VERSION 5.8 ;
BUSBITCHARS "[]" ;
DIVIDERCHAR "/" ;

PROPERTYDEFINITIONS
  MACRO SDLpower STRING ;
  MACRO SDLground STRING ;
  MACRO SDLglobal STRING ;
END PROPERTYDEFINITIONS

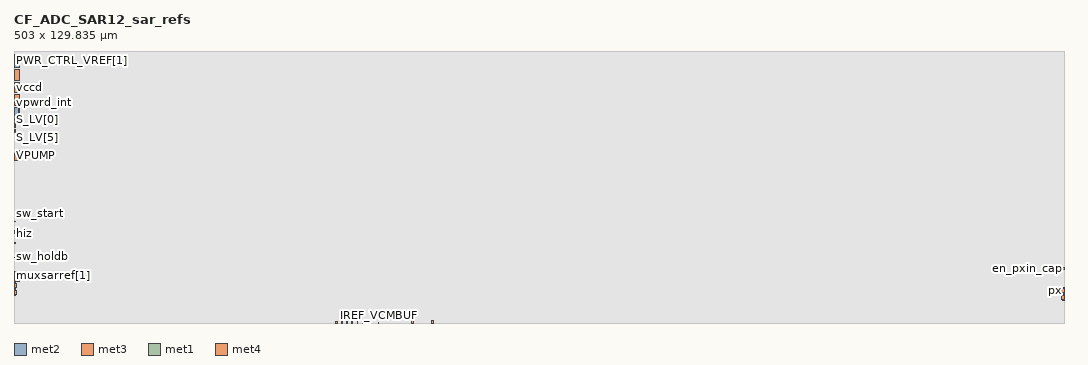
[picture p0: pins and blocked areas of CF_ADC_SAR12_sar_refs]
MACRO CF_ADC_SAR12_sar_refs
  ORIGIN 0 0 ;
  FOREIGN CF_ADC_SAR12_sar_refs 0 0 ;
  SIZE 503 BY 129.835 ;
  PIN vdda
    DIRECTION INOUT ;
    USE POWER ;
    PORT
      LAYER met2 ;
        RECT 0 122.39 2.5 127.085 ;
      LAYER met3 ;
        RECT 0 122.39 2.5 127.14 ;
    END
  END vdda
  PIN vda_int
    DIRECTION OUTPUT ;
    USE POWER ;
    PORT
      LAYER met2 ;
        RECT 0 116.39 2.5 121.39 ;
      LAYER met3 ;
        RECT 0 116.39 2.5 121.39 ;
    END
  END vda_int
  PIN vccd
    DIRECTION INOUT ;
    USE POWER ;
    PORT
      LAYER met2 ;
        RECT 0 110.39 2.5 115.39 ;
      LAYER met3 ;
        RECT 0 110.39 2.5 115.39 ;
    END
  END vccd
  PIN vpwrd_int
    DIRECTION OUTPUT ;
    USE POWER ;
    PORT
      LAYER met2 ;
        RECT 0 104.39 2.5 109.39 ;
      LAYER met3 ;
        RECT 0 104.39 2.5 109.39 ;
    END
  END vpwrd_int
  PIN VPUMP
    DIRECTION INOUT ;
    USE POWER ;
    PORT
      LAYER met2 ;
        RECT 0 77.69 2.5 82.69 ;
      LAYER met3 ;
        RECT 0 77.69 2.5 82.69 ;
    END
  END VPUMP
  PIN vssa
    DIRECTION INOUT ;
    USE GROUND ;
    PORT
      LAYER met3 ;
        RECT 502.505 16.9 503 17.18 ;
      LAYER met2 ;
        RECT 502.505 16.9 503 17.18 ;
      LAYER met3 ;
        RECT 502.505 13.77 503 14.05 ;
      LAYER met2 ;
        RECT 502.505 13.77 503 14.05 ;
      LAYER met3 ;
        RECT 502.505 10.64 503 10.92 ;
      LAYER met2 ;
        RECT 502.505 10.64 503 10.92 ;
      LAYER met3 ;
        RECT 0 13.05 0.495 13.33 ;
      LAYER met2 ;
        RECT 0 13.05 0.495 13.33 ;
      LAYER met3 ;
        RECT 0 16.18 0.495 16.46 ;
      LAYER met2 ;
        RECT 0 16.18 0.495 16.46 ;
        RECT 0 19.31 0.495 19.59 ;
      LAYER met3 ;
        RECT 0 19.31 0.495 19.59 ;
      LAYER met2 ;
        RECT 0 98.475 2.38 103.39 ;
      LAYER met3 ;
        RECT 0 98.475 2.5 103.39 ;
    END
  END vssa
  PIN vssd
    DIRECTION INOUT ;
    USE GROUND ;
    PORT
      LAYER met3 ;
        RECT 0 20.045 2.5 24.695 ;
    END
  END vssd
  PIN vref[4]
    DIRECTION INPUT ;
    USE SIGNAL ;
    PORT
      LAYER met3 ;
        RECT 166.94 0 167.245 0.715 ;
    END
  END vref[4]
  PIN vref[3]
    DIRECTION INPUT ;
    USE SIGNAL ;
    PORT
      LAYER met3 ;
        RECT 164.425 0 164.73 0.715 ;
    END
  END vref[3]
  PIN vref[2]
    DIRECTION INPUT ;
    USE SIGNAL ;
    PORT
      LAYER met3 ;
        RECT 161.89 0 162.195 0.715 ;
    END
  END vref[2]
  PIN vref[1]
    DIRECTION INPUT ;
    USE SIGNAL ;
    PORT
      LAYER met3 ;
        RECT 159.385 0 159.69 0.715 ;
    END
  END vref[1]
  PIN vref[0]
    DIRECTION INPUT ;
    USE SIGNAL ;
    PORT
      LAYER met3 ;
        RECT 156.875 0 157.18 0.715 ;
    END
  END vref[0]
  PIN pd
    DIRECTION INPUT ;
    USE SIGNAL ;
    PORT
      LAYER met3 ;
        RECT 0 43.53 0.715 43.79 ;
      LAYER met2 ;
        RECT 0 43.53 0.715 43.79 ;
    END
  END pd
  PIN hiz
    DIRECTION INPUT ;
    USE SIGNAL ;
    PORT
      LAYER met3 ;
        RECT 0 42.9 0.715 43.16 ;
      LAYER met2 ;
        RECT 0 42.9 0.715 43.16 ;
    END
  END hiz
  PIN PWR_CTRL_VREF[1]
    DIRECTION INPUT ;
    USE SIGNAL ;
    PORT
      LAYER met1 ;
        RECT 0 127.865 0.22 127.965 ;
      LAYER met2 ;
        RECT 0 127.865 0.22 127.965 ;
    END
  END PWR_CTRL_VREF[1]
  PIN muxsarref[2]
    DIRECTION INPUT ;
    USE SIGNAL ;
    PORT
      LAYER met2 ;
        RECT 0 23.87 0.715 24.13 ;
    END
  END muxsarref[2]
  PIN muxsarref[1]
    DIRECTION INPUT ;
    USE SIGNAL ;
    PORT
      LAYER met2 ;
        RECT 0 22.685 0.715 22.935 ;
    END
  END muxsarref[1]
  PIN muxsarref[0]
    DIRECTION INPUT ;
    USE SIGNAL ;
    PORT
      LAYER met2 ;
        RECT 0 23.445 0.715 23.705 ;
    END
  END muxsarref[0]
  PIN REFBY2
    DIRECTION OUTPUT ;
    USE SIGNAL ;
    PORT
      LAYER met3 ;
        RECT 154.165 0 154.885 0.755 ;
    END
  END REFBY2
  PIN pd_ana
    DIRECTION INPUT ;
    USE SIGNAL ;
    PORT
      LAYER met3 ;
        RECT 0 44.16 0.715 44.42 ;
      LAYER met2 ;
        RECT 0 44.16 0.715 44.42 ;
    END
  END pd_ana
  PIN EN_RESVDA
    DIRECTION INPUT ;
    USE SIGNAL ;
    PORT
      LAYER met1 ;
        RECT 0 128.67 0.33 128.825 ;
      LAYER met2 ;
        RECT 0 128.67 0.33 128.825 ;
    END
  END EN_RESVDA
  PIN IREF_VCMBUF
    DIRECTION INPUT ;
    USE SIGNAL ;
    PORT
      LAYER met3 ;
        RECT 174.5 0 174.73 0.395 ;
    END
  END IREF_VCMBUF
  PIN sw_start
    DIRECTION INPUT ;
    USE SIGNAL ;
    PORT
      LAYER met3 ;
        RECT 0 48.52 0.715 48.78 ;
      LAYER met2 ;
        RECT 0 48.52 0.715 48.78 ;
    END
  END sw_start
  PIN PWR_CTRL_VREF[0]
    DIRECTION INPUT ;
    USE SIGNAL ;
    PORT
      LAYER met1 ;
        RECT 0 127.44 0.22 127.56 ;
      LAYER met2 ;
        RECT 0 127.44 0.22 127.56 ;
    END
  END PWR_CTRL_VREF[0]
  PIN pd_vcmbuf
    DIRECTION INPUT ;
    USE SIGNAL ;
    PORT
      LAYER met1 ;
        RECT 0 129.1 0.285 129.245 ;
      LAYER met2 ;
        RECT 0 129.1 0.285 129.245 ;
    END
  END pd_vcmbuf
  PIN S_LV[7]
    DIRECTION INPUT ;
    USE SIGNAL ;
    PORT
      LAYER met2 ;
        RECT 0 94.16 0.915 94.49 ;
      LAYER met3 ;
        RECT 0 94.16 0.915 94.49 ;
    END
  END S_LV[7]
  PIN px_in
    DIRECTION INOUT ;
    USE SIGNAL ;
    PORT
      LAYER met2 ;
        RECT 501.565 11.35 503 13.35 ;
      LAYER met3 ;
        RECT 501.565 11.35 503 13.35 ;
      LAYER met2 ;
        RECT 0 13.8 1.435 15.71 ;
      LAYER met3 ;
        RECT 0 13.8 1.435 15.71 ;
    END
  END px_in
  PIN px
    DIRECTION INOUT ;
    USE SIGNAL ;
    PORT
      LAYER met2 ;
        RECT 501.565 14.47 503 16.47 ;
      LAYER met3 ;
        RECT 501.565 14.47 503 16.47 ;
      LAYER met2 ;
        RECT 0 16.935 1.435 18.845 ;
      LAYER met3 ;
        RECT 0 16.935 1.435 18.845 ;
    END
  END px
  PIN refout
    DIRECTION OUTPUT ;
    USE SIGNAL ;
    PORT
      LAYER met4 ;
        RECT 190.37 0 191.37 1.39 ;
    END
  END refout
  PIN refout_en
    DIRECTION INPUT ;
    USE SIGNAL ;
    PORT
      LAYER met3 ;
        RECT 0 38.295 0.715 38.555 ;
      LAYER met2 ;
        RECT 0 38.295 0.715 38.555 ;
    END
  END refout_en
  PIN sw_holdb
    DIRECTION INPUT ;
    USE SIGNAL ;
    PORT
      LAYER met3 ;
        RECT 0 31.835 0.39 32.095 ;
      LAYER met2 ;
        RECT 0 31.835 0.39 32.095 ;
    END
  END sw_holdb
  PIN enpdb_hv
    DIRECTION INPUT ;
    USE SIGNAL ;
    PORT
      LAYER met3 ;
        RECT 0 31.22 0.585 31.41 ;
      LAYER met2 ;
        RECT 0 31.22 0.585 31.41 ;
    END
  END enpdb_hv
  PIN en_pxin_cap
    DIRECTION OUTPUT ;
    USE SIGNAL ;
    PORT
      LAYER met2 ;
        RECT 502.03 25.72 503 26.72 ;
    END
  END en_pxin_cap
  PIN S_LV[6]
    DIRECTION INPUT ;
    USE SIGNAL ;
    PORT
      LAYER met2 ;
        RECT 0 91.89 0.915 92.22 ;
      LAYER met3 ;
        RECT 0 91.89 0.915 92.22 ;
    END
  END S_LV[6]
  PIN S_LV[5]
    DIRECTION INPUT ;
    USE SIGNAL ;
    PORT
      LAYER met2 ;
        RECT 0 92.52 0.915 92.85 ;
      LAYER met3 ;
        RECT 0 92.52 0.915 92.85 ;
    END
  END S_LV[5]
  PIN S_LV[4]
    DIRECTION INPUT ;
    USE SIGNAL ;
    PORT
      LAYER met2 ;
        RECT 0 94.84 0.915 95.17 ;
      LAYER met3 ;
        RECT 0 94.84 0.915 95.17 ;
    END
  END S_LV[4]
  PIN S_LV[3]
    DIRECTION INPUT ;
    USE SIGNAL ;
    PORT
      LAYER met2 ;
        RECT 0 95.52 0.915 95.85 ;
      LAYER met3 ;
        RECT 0 95.52 0.915 95.85 ;
    END
  END S_LV[3]
  PIN S_LV[2]
    DIRECTION INPUT ;
    USE SIGNAL ;
    PORT
      LAYER met2 ;
        RECT 0 96.2 0.915 96.53 ;
      LAYER met3 ;
        RECT 0 96.2 0.915 96.53 ;
    END
  END S_LV[2]
  PIN S_LV[1]
    DIRECTION INPUT ;
    USE SIGNAL ;
    PORT
      LAYER met2 ;
        RECT 0 96.88 0.915 97.21 ;
      LAYER met3 ;
        RECT 0 96.88 0.915 97.21 ;
    END
  END S_LV[1]
  PIN S_LV[0]
    DIRECTION INPUT ;
    USE SIGNAL ;
    PORT
      LAYER met2 ;
        RECT 0 97.56 0.915 97.89 ;
      LAYER met3 ;
        RECT 0 97.56 0.915 97.89 ;
    END
  END S_LV[0]
  PIN REFHI
    DIRECTION OUTPUT ;
    USE SIGNAL ;
    PORT
      LAYER met4 ;
        RECT 199.905 0 200.905 1.39 ;
    END
  END REFHI
  PIN enable_hv
    DIRECTION INPUT ;
    USE SIGNAL ;
    PORT
      LAYER met1 ;
        RECT 0 129.51 0.255 129.675 ;
      LAYER met2 ;
        RECT 0 129.51 0.255 129.675 ;
    END
  END enable_hv
  PIN IREF_VREFBUF
    DIRECTION INPUT ;
    USE SIGNAL ;
    PORT
      LAYER met3 ;
        RECT 169.42 0 169.72 0.715 ;
    END
  END IREF_VREFBUF
  PIN PD_BUF_VREF
    DIRECTION INPUT ;
    USE SIGNAL ;
    PORT
      LAYER met1 ;
        RECT 0 128.28 0.245 128.395 ;
      LAYER met2 ;
        RECT 0 128.28 0.245 128.395 ;
    END
  END PD_BUF_VREF
  PIN vssa_shield
    DIRECTION INOUT ;
    USE GROUND ;
    PORT
      LAYER met2 ;
        RECT 0 91.26 0.915 91.59 ;
      LAYER met3 ;
        RECT 0 91.26 0.915 91.59 ;
    END
  END vssa_shield
  PIN dft_comp_en
    DIRECTION INPUT ;
    USE SIGNAL ;
    PORT
      LAYER met2 ;
        RECT 0 93.48 0.915 93.81 ;
      LAYER met3 ;
        RECT 0 93.48 0.915 93.81 ;
    END
  END dft_comp_en
  PROPERTY SDLpower "VPUMP vccd vda_int vdda vpwrd_int" ;
  PROPERTY SDLground "vssa vssa_shield vssd" ;
  PROPERTY SDLglobal "" ;
  OBS
    LAYER li1 ;
      RECT 0 0 503 129.835 ;
    LAYER met1 ;
      RECT 0 0 0.22 127.44 ;
      RECT 0 127.56 0.22 127.865 ;
      RECT 0 127.965 0.22 128.28 ;
      RECT 0 128.395 0.22 128.67 ;
      RECT 0 128.825 0.22 129.1 ;
      RECT 0 129.245 0.22 129.51 ;
      RECT 0 129.675 0.22 129.835 ;
      RECT 0.22 0 0.245 128.28 ;
      RECT 0.22 128.395 0.245 128.67 ;
      RECT 0.22 128.825 0.245 129.1 ;
      RECT 0.22 129.245 0.245 129.51 ;
      RECT 0.22 129.675 0.245 129.835 ;
      RECT 0.245 0 0.255 128.67 ;
      RECT 0.245 128.825 0.255 129.1 ;
      RECT 0.245 129.245 0.255 129.51 ;
      RECT 0.245 129.675 0.255 129.835 ;
      RECT 0.255 0 0.285 128.67 ;
      RECT 0.255 128.825 0.285 129.1 ;
      RECT 0.255 129.245 0.285 129.835 ;
      RECT 0.285 0 0.33 128.67 ;
      RECT 0.285 128.825 0.33 129.835 ;
      RECT 0.33 0 503 129.835 ;
    LAYER met2 ;
      RECT 0 0 0.22 13.05 ;
      RECT 0 13.33 0.22 13.8 ;
      RECT 0 15.71 0.22 16.18 ;
      RECT 0 16.46 0.22 16.935 ;
      RECT 0 18.845 0.22 19.31 ;
      RECT 0 19.59 0.22 22.685 ;
      RECT 0 22.935 0.22 23.445 ;
      RECT 0 23.705 0.22 23.87 ;
      RECT 0 24.13 0.22 31.22 ;
      RECT 0 31.41 0.22 31.835 ;
      RECT 0 32.095 0.22 38.295 ;
      RECT 0 38.555 0.22 42.9 ;
      RECT 0 43.16 0.22 43.53 ;
      RECT 0 43.79 0.22 44.16 ;
      RECT 0 44.42 0.22 48.52 ;
      RECT 0 48.78 0.22 77.69 ;
      RECT 0 82.69 0.22 91.26 ;
      RECT 0 91.59 0.22 91.89 ;
      RECT 0 92.22 0.22 92.52 ;
      RECT 0 92.85 0.22 93.48 ;
      RECT 0 93.81 0.22 94.16 ;
      RECT 0 94.49 0.22 94.84 ;
      RECT 0 95.17 0.22 95.52 ;
      RECT 0 95.85 0.22 96.2 ;
      RECT 0 96.53 0.22 96.88 ;
      RECT 0 97.21 0.22 97.56 ;
      RECT 0 97.89 0.22 98.475 ;
      RECT 0 103.39 0.22 104.39 ;
      RECT 0 109.39 0.22 110.39 ;
      RECT 0 115.39 0.22 116.39 ;
      RECT 0 121.39 0.22 122.39 ;
      RECT 0 127.085 0.22 127.44 ;
      RECT 0 127.56 0.22 127.865 ;
      RECT 0 127.965 0.22 128.28 ;
      RECT 0 128.395 0.22 128.67 ;
      RECT 0 128.825 0.22 129.1 ;
      RECT 0 129.245 0.22 129.51 ;
      RECT 0 129.675 0.22 129.835 ;
      RECT 0.22 0 0.245 13.05 ;
      RECT 0.22 13.33 0.245 13.8 ;
      RECT 0.22 15.71 0.245 16.18 ;
      RECT 0.22 16.46 0.245 16.935 ;
      RECT 0.22 18.845 0.245 19.31 ;
      RECT 0.22 19.59 0.245 22.685 ;
      RECT 0.22 22.935 0.245 23.445 ;
      RECT 0.22 23.705 0.245 23.87 ;
      RECT 0.22 24.13 0.245 31.22 ;
      RECT 0.22 31.41 0.245 31.835 ;
      RECT 0.22 32.095 0.245 38.295 ;
      RECT 0.22 38.555 0.245 42.9 ;
      RECT 0.22 43.16 0.245 43.53 ;
      RECT 0.22 43.79 0.245 44.16 ;
      RECT 0.22 44.42 0.245 48.52 ;
      RECT 0.22 48.78 0.245 77.69 ;
      RECT 0.22 82.69 0.245 91.26 ;
      RECT 0.22 91.59 0.245 91.89 ;
      RECT 0.22 92.22 0.245 92.52 ;
      RECT 0.22 92.85 0.245 93.48 ;
      RECT 0.22 93.81 0.245 94.16 ;
      RECT 0.22 94.49 0.245 94.84 ;
      RECT 0.22 95.17 0.245 95.52 ;
      RECT 0.22 95.85 0.245 96.2 ;
      RECT 0.22 96.53 0.245 96.88 ;
      RECT 0.22 97.21 0.245 97.56 ;
      RECT 0.22 97.89 0.245 98.475 ;
      RECT 0.22 103.39 0.245 104.39 ;
      RECT 0.22 109.39 0.245 110.39 ;
      RECT 0.22 115.39 0.245 116.39 ;
      RECT 0.22 121.39 0.245 122.39 ;
      RECT 0.22 127.085 0.245 128.28 ;
      RECT 0.22 128.395 0.245 128.67 ;
      RECT 0.22 128.825 0.245 129.1 ;
      RECT 0.22 129.245 0.245 129.51 ;
      RECT 0.22 129.675 0.245 129.835 ;
      RECT 0.245 0 0.255 13.05 ;
      RECT 0.245 13.33 0.255 13.8 ;
      RECT 0.245 15.71 0.255 16.18 ;
      RECT 0.245 16.46 0.255 16.935 ;
      RECT 0.245 18.845 0.255 19.31 ;
      RECT 0.245 19.59 0.255 22.685 ;
      RECT 0.245 22.935 0.255 23.445 ;
      RECT 0.245 23.705 0.255 23.87 ;
      RECT 0.245 24.13 0.255 31.22 ;
      RECT 0.245 31.41 0.255 31.835 ;
      RECT 0.245 32.095 0.255 38.295 ;
      RECT 0.245 38.555 0.255 42.9 ;
      RECT 0.245 43.16 0.255 43.53 ;
      RECT 0.245 43.79 0.255 44.16 ;
      RECT 0.245 44.42 0.255 48.52 ;
      RECT 0.245 48.78 0.255 77.69 ;
      RECT 0.245 82.69 0.255 91.26 ;
      RECT 0.245 91.59 0.255 91.89 ;
      RECT 0.245 92.22 0.255 92.52 ;
      RECT 0.245 92.85 0.255 93.48 ;
      RECT 0.245 93.81 0.255 94.16 ;
      RECT 0.245 94.49 0.255 94.84 ;
      RECT 0.245 95.17 0.255 95.52 ;
      RECT 0.245 95.85 0.255 96.2 ;
      RECT 0.245 96.53 0.255 96.88 ;
      RECT 0.245 97.21 0.255 97.56 ;
      RECT 0.245 97.89 0.255 98.475 ;
      RECT 0.245 103.39 0.255 104.39 ;
      RECT 0.245 109.39 0.255 110.39 ;
      RECT 0.245 115.39 0.255 116.39 ;
      RECT 0.245 121.39 0.255 122.39 ;
      RECT 0.245 127.085 0.255 128.67 ;
      RECT 0.245 128.825 0.255 129.1 ;
      RECT 0.245 129.245 0.255 129.51 ;
      RECT 0.245 129.675 0.255 129.835 ;
      RECT 0.255 0 0.285 13.05 ;
      RECT 0.255 13.33 0.285 13.8 ;
      RECT 0.255 15.71 0.285 16.18 ;
      RECT 0.255 16.46 0.285 16.935 ;
      RECT 0.255 18.845 0.285 19.31 ;
      RECT 0.255 19.59 0.285 22.685 ;
      RECT 0.255 22.935 0.285 23.445 ;
      RECT 0.255 23.705 0.285 23.87 ;
      RECT 0.255 24.13 0.285 31.22 ;
      RECT 0.255 31.41 0.285 31.835 ;
      RECT 0.255 32.095 0.285 38.295 ;
      RECT 0.255 38.555 0.285 42.9 ;
      RECT 0.255 43.16 0.285 43.53 ;
      RECT 0.255 43.79 0.285 44.16 ;
      RECT 0.255 44.42 0.285 48.52 ;
      RECT 0.255 48.78 0.285 77.69 ;
      RECT 0.255 82.69 0.285 91.26 ;
      RECT 0.255 91.59 0.285 91.89 ;
      RECT 0.255 92.22 0.285 92.52 ;
      RECT 0.255 92.85 0.285 93.48 ;
      RECT 0.255 93.81 0.285 94.16 ;
      RECT 0.255 94.49 0.285 94.84 ;
      RECT 0.255 95.17 0.285 95.52 ;
      RECT 0.255 95.85 0.285 96.2 ;
      RECT 0.255 96.53 0.285 96.88 ;
      RECT 0.255 97.21 0.285 97.56 ;
      RECT 0.255 97.89 0.285 98.475 ;
      RECT 0.255 103.39 0.285 104.39 ;
      RECT 0.255 109.39 0.285 110.39 ;
      RECT 0.255 115.39 0.285 116.39 ;
      RECT 0.255 121.39 0.285 122.39 ;
      RECT 0.255 127.085 0.285 128.67 ;
      RECT 0.255 128.825 0.285 129.1 ;
      RECT 0.255 129.245 0.285 129.835 ;
      RECT 0.285 0 0.33 13.05 ;
      RECT 0.285 13.33 0.33 13.8 ;
      RECT 0.285 15.71 0.33 16.18 ;
      RECT 0.285 16.46 0.33 16.935 ;
      RECT 0.285 18.845 0.33 19.31 ;
      RECT 0.285 19.59 0.33 22.685 ;
      RECT 0.285 22.935 0.33 23.445 ;
      RECT 0.285 23.705 0.33 23.87 ;
      RECT 0.285 24.13 0.33 31.22 ;
      RECT 0.285 31.41 0.33 31.835 ;
      RECT 0.285 32.095 0.33 38.295 ;
      RECT 0.285 38.555 0.33 42.9 ;
      RECT 0.285 43.16 0.33 43.53 ;
      RECT 0.285 43.79 0.33 44.16 ;
      RECT 0.285 44.42 0.33 48.52 ;
      RECT 0.285 48.78 0.33 77.69 ;
      RECT 0.285 82.69 0.33 91.26 ;
      RECT 0.285 91.59 0.33 91.89 ;
      RECT 0.285 92.22 0.33 92.52 ;
      RECT 0.285 92.85 0.33 93.48 ;
      RECT 0.285 93.81 0.33 94.16 ;
      RECT 0.285 94.49 0.33 94.84 ;
      RECT 0.285 95.17 0.33 95.52 ;
      RECT 0.285 95.85 0.33 96.2 ;
      RECT 0.285 96.53 0.33 96.88 ;
      RECT 0.285 97.21 0.33 97.56 ;
      RECT 0.285 97.89 0.33 98.475 ;
      RECT 0.285 103.39 0.33 104.39 ;
      RECT 0.285 109.39 0.33 110.39 ;
      RECT 0.285 115.39 0.33 116.39 ;
      RECT 0.285 121.39 0.33 122.39 ;
      RECT 0.285 127.085 0.33 128.67 ;
      RECT 0.285 128.825 0.33 129.835 ;
      RECT 0.33 0 0.39 13.05 ;
      RECT 0.33 13.33 0.39 13.8 ;
      RECT 0.33 15.71 0.39 16.18 ;
      RECT 0.33 16.46 0.39 16.935 ;
      RECT 0.33 18.845 0.39 19.31 ;
      RECT 0.33 19.59 0.39 22.685 ;
      RECT 0.33 22.935 0.39 23.445 ;
      RECT 0.33 23.705 0.39 23.87 ;
      RECT 0.33 24.13 0.39 31.22 ;
      RECT 0.33 31.41 0.39 31.835 ;
      RECT 0.33 32.095 0.39 38.295 ;
      RECT 0.33 38.555 0.39 42.9 ;
      RECT 0.33 43.16 0.39 43.53 ;
      RECT 0.33 43.79 0.39 44.16 ;
      RECT 0.33 44.42 0.39 48.52 ;
      RECT 0.33 48.78 0.39 77.69 ;
      RECT 0.33 82.69 0.39 91.26 ;
      RECT 0.33 91.59 0.39 91.89 ;
      RECT 0.33 92.22 0.39 92.52 ;
      RECT 0.33 92.85 0.39 93.48 ;
      RECT 0.33 93.81 0.39 94.16 ;
      RECT 0.33 94.49 0.39 94.84 ;
      RECT 0.33 95.17 0.39 95.52 ;
      RECT 0.33 95.85 0.39 96.2 ;
      RECT 0.33 96.53 0.39 96.88 ;
      RECT 0.33 97.21 0.39 97.56 ;
      RECT 0.33 97.89 0.39 98.475 ;
      RECT 0.33 103.39 0.39 104.39 ;
      RECT 0.33 109.39 0.39 110.39 ;
      RECT 0.33 115.39 0.39 116.39 ;
      RECT 0.33 121.39 0.39 122.39 ;
      RECT 0.33 127.085 0.39 129.835 ;
      RECT 0.39 0 0.495 13.05 ;
      RECT 0.39 13.33 0.495 13.8 ;
      RECT 0.39 15.71 0.495 16.18 ;
      RECT 0.39 16.46 0.495 16.935 ;
      RECT 0.39 18.845 0.495 19.31 ;
      RECT 0.39 19.59 0.495 22.685 ;
      RECT 0.39 22.935 0.495 23.445 ;
      RECT 0.39 23.705 0.495 23.87 ;
      RECT 0.39 24.13 0.495 31.22 ;
      RECT 0.39 31.41 0.495 38.295 ;
      RECT 0.39 38.555 0.495 42.9 ;
      RECT 0.39 43.16 0.495 43.53 ;
      RECT 0.39 43.79 0.495 44.16 ;
      RECT 0.39 44.42 0.495 48.52 ;
      RECT 0.39 48.78 0.495 77.69 ;
      RECT 0.39 82.69 0.495 91.26 ;
      RECT 0.39 91.59 0.495 91.89 ;
      RECT 0.39 92.22 0.495 92.52 ;
      RECT 0.39 92.85 0.495 93.48 ;
      RECT 0.39 93.81 0.495 94.16 ;
      RECT 0.39 94.49 0.495 94.84 ;
      RECT 0.39 95.17 0.495 95.52 ;
      RECT 0.39 95.85 0.495 96.2 ;
      RECT 0.39 96.53 0.495 96.88 ;
      RECT 0.39 97.21 0.495 97.56 ;
      RECT 0.39 97.89 0.495 98.475 ;
      RECT 0.39 103.39 0.495 104.39 ;
      RECT 0.39 109.39 0.495 110.39 ;
      RECT 0.39 115.39 0.495 116.39 ;
      RECT 0.39 121.39 0.495 122.39 ;
      RECT 0.39 127.085 0.495 129.835 ;
      RECT 0.495 0 0.585 13.8 ;
      RECT 0.495 15.71 0.585 16.935 ;
      RECT 0.495 18.845 0.585 22.685 ;
      RECT 0.495 22.935 0.585 23.445 ;
      RECT 0.495 23.705 0.585 23.87 ;
      RECT 0.495 24.13 0.585 31.22 ;
      RECT 0.495 31.41 0.585 38.295 ;
      RECT 0.495 38.555 0.585 42.9 ;
      RECT 0.495 43.16 0.585 43.53 ;
      RECT 0.495 43.79 0.585 44.16 ;
      RECT 0.495 44.42 0.585 48.52 ;
      RECT 0.495 48.78 0.585 77.69 ;
      RECT 0.495 82.69 0.585 91.26 ;
      RECT 0.495 91.59 0.585 91.89 ;
      RECT 0.495 92.22 0.585 92.52 ;
      RECT 0.495 92.85 0.585 93.48 ;
      RECT 0.495 93.81 0.585 94.16 ;
      RECT 0.495 94.49 0.585 94.84 ;
      RECT 0.495 95.17 0.585 95.52 ;
      RECT 0.495 95.85 0.585 96.2 ;
      RECT 0.495 96.53 0.585 96.88 ;
      RECT 0.495 97.21 0.585 97.56 ;
      RECT 0.495 97.89 0.585 98.475 ;
      RECT 0.495 103.39 0.585 104.39 ;
      RECT 0.495 109.39 0.585 110.39 ;
      RECT 0.495 115.39 0.585 116.39 ;
      RECT 0.495 121.39 0.585 122.39 ;
      RECT 0.495 127.085 0.585 129.835 ;
      RECT 0.585 0 0.715 13.8 ;
      RECT 0.585 15.71 0.715 16.935 ;
      RECT 0.585 18.845 0.715 22.685 ;
      RECT 0.585 22.935 0.715 23.445 ;
      RECT 0.585 23.705 0.715 23.87 ;
      RECT 0.585 24.13 0.715 38.295 ;
      RECT 0.585 38.555 0.715 42.9 ;
      RECT 0.585 43.16 0.715 43.53 ;
      RECT 0.585 43.79 0.715 44.16 ;
      RECT 0.585 44.42 0.715 48.52 ;
      RECT 0.585 48.78 0.715 77.69 ;
      RECT 0.585 82.69 0.715 91.26 ;
      RECT 0.585 91.59 0.715 91.89 ;
      RECT 0.585 92.22 0.715 92.52 ;
      RECT 0.585 92.85 0.715 93.48 ;
      RECT 0.585 93.81 0.715 94.16 ;
      RECT 0.585 94.49 0.715 94.84 ;
      RECT 0.585 95.17 0.715 95.52 ;
      RECT 0.585 95.85 0.715 96.2 ;
      RECT 0.585 96.53 0.715 96.88 ;
      RECT 0.585 97.21 0.715 97.56 ;
      RECT 0.585 97.89 0.715 98.475 ;
      RECT 0.585 103.39 0.715 104.39 ;
      RECT 0.585 109.39 0.715 110.39 ;
      RECT 0.585 115.39 0.715 116.39 ;
      RECT 0.585 121.39 0.715 122.39 ;
      RECT 0.585 127.085 0.715 129.835 ;
      RECT 0.715 0 0.915 13.8 ;
      RECT 0.715 15.71 0.915 16.935 ;
      RECT 0.715 18.845 0.915 77.69 ;
      RECT 0.715 82.69 0.915 91.26 ;
      RECT 0.715 91.59 0.915 91.89 ;
      RECT 0.715 92.22 0.915 92.52 ;
      RECT 0.715 92.85 0.915 93.48 ;
      RECT 0.715 93.81 0.915 94.16 ;
      RECT 0.715 94.49 0.915 94.84 ;
      RECT 0.715 95.17 0.915 95.52 ;
      RECT 0.715 95.85 0.915 96.2 ;
      RECT 0.715 96.53 0.915 96.88 ;
      RECT 0.715 97.21 0.915 97.56 ;
      RECT 0.715 97.89 0.915 98.475 ;
      RECT 0.715 103.39 0.915 104.39 ;
      RECT 0.715 109.39 0.915 110.39 ;
      RECT 0.715 115.39 0.915 116.39 ;
      RECT 0.715 121.39 0.915 122.39 ;
      RECT 0.715 127.085 0.915 129.835 ;
      RECT 0.915 0 1.435 13.8 ;
      RECT 0.915 15.71 1.435 16.935 ;
      RECT 0.915 18.845 1.435 77.69 ;
      RECT 0.915 82.69 1.435 98.475 ;
      RECT 0.915 103.39 1.435 104.39 ;
      RECT 0.915 109.39 1.435 110.39 ;
      RECT 0.915 115.39 1.435 116.39 ;
      RECT 0.915 121.39 1.435 122.39 ;
      RECT 0.915 127.085 1.435 129.835 ;
      RECT 1.435 0 2.38 77.69 ;
      RECT 1.435 82.69 2.38 98.475 ;
      RECT 1.435 103.39 2.38 104.39 ;
      RECT 1.435 109.39 2.38 110.39 ;
      RECT 1.435 115.39 2.38 116.39 ;
      RECT 1.435 121.39 2.38 122.39 ;
      RECT 1.435 127.085 2.38 129.835 ;
      RECT 2.38 0 2.5 77.69 ;
      RECT 2.38 82.69 2.5 104.39 ;
      RECT 2.38 109.39 2.5 110.39 ;
      RECT 2.38 115.39 2.5 116.39 ;
      RECT 2.38 121.39 2.5 122.39 ;
      RECT 2.38 127.085 2.5 129.835 ;
      RECT 2.5 0 501.565 129.835 ;
      RECT 501.565 0 502.03 11.35 ;
      RECT 501.565 13.35 502.03 14.47 ;
      RECT 501.565 16.47 502.03 129.835 ;
      RECT 502.03 0 502.505 11.35 ;
      RECT 502.03 13.35 502.505 14.47 ;
      RECT 502.03 16.47 502.505 25.72 ;
      RECT 502.03 26.72 502.505 129.835 ;
      RECT 502.505 0 503 10.64 ;
      RECT 502.505 10.92 503 11.35 ;
      RECT 502.505 13.35 503 13.77 ;
      RECT 502.505 14.05 503 14.47 ;
      RECT 502.505 16.47 503 16.9 ;
      RECT 502.505 17.18 503 25.72 ;
      RECT 502.505 26.72 503 129.835 ;
    LAYER met3 ;
      RECT 0 0 0.39 13.05 ;
      RECT 0 13.33 0.39 13.8 ;
      RECT 0 15.71 0.39 16.18 ;
      RECT 0 16.46 0.39 16.935 ;
      RECT 0 18.845 0.39 19.31 ;
      RECT 0 19.59 0.39 20.045 ;
      RECT 0 24.695 0.39 31.22 ;
      RECT 0 31.41 0.39 31.835 ;
      RECT 0 32.095 0.39 38.295 ;
      RECT 0 38.555 0.39 42.9 ;
      RECT 0 43.16 0.39 43.53 ;
      RECT 0 43.79 0.39 44.16 ;
      RECT 0 44.42 0.39 48.52 ;
      RECT 0 48.78 0.39 77.69 ;
      RECT 0 82.69 0.39 91.26 ;
      RECT 0 91.59 0.39 91.89 ;
      RECT 0 92.22 0.39 92.52 ;
      RECT 0 92.85 0.39 93.48 ;
      RECT 0 93.81 0.39 94.16 ;
      RECT 0 94.49 0.39 94.84 ;
      RECT 0 95.17 0.39 95.52 ;
      RECT 0 95.85 0.39 96.2 ;
      RECT 0 96.53 0.39 96.88 ;
      RECT 0 97.21 0.39 97.56 ;
      RECT 0 97.89 0.39 98.475 ;
      RECT 0 103.39 0.39 104.39 ;
      RECT 0 109.39 0.39 110.39 ;
      RECT 0 115.39 0.39 116.39 ;
      RECT 0 121.39 0.39 122.39 ;
      RECT 0 127.14 0.39 129.835 ;
      RECT 0.39 0 0.495 13.05 ;
      RECT 0.39 13.33 0.495 13.8 ;
      RECT 0.39 15.71 0.495 16.18 ;
      RECT 0.39 16.46 0.495 16.935 ;
      RECT 0.39 18.845 0.495 19.31 ;
      RECT 0.39 19.59 0.495 20.045 ;
      RECT 0.39 24.695 0.495 31.22 ;
      RECT 0.39 31.41 0.495 38.295 ;
      RECT 0.39 38.555 0.495 42.9 ;
      RECT 0.39 43.16 0.495 43.53 ;
      RECT 0.39 43.79 0.495 44.16 ;
      RECT 0.39 44.42 0.495 48.52 ;
      RECT 0.39 48.78 0.495 77.69 ;
      RECT 0.39 82.69 0.495 91.26 ;
      RECT 0.39 91.59 0.495 91.89 ;
      RECT 0.39 92.22 0.495 92.52 ;
      RECT 0.39 92.85 0.495 93.48 ;
      RECT 0.39 93.81 0.495 94.16 ;
      RECT 0.39 94.49 0.495 94.84 ;
      RECT 0.39 95.17 0.495 95.52 ;
      RECT 0.39 95.85 0.495 96.2 ;
      RECT 0.39 96.53 0.495 96.88 ;
      RECT 0.39 97.21 0.495 97.56 ;
      RECT 0.39 97.89 0.495 98.475 ;
      RECT 0.39 103.39 0.495 104.39 ;
      RECT 0.39 109.39 0.495 110.39 ;
      RECT 0.39 115.39 0.495 116.39 ;
      RECT 0.39 121.39 0.495 122.39 ;
      RECT 0.39 127.14 0.495 129.835 ;
      RECT 0.495 0 0.585 13.8 ;
      RECT 0.495 15.71 0.585 16.935 ;
      RECT 0.495 18.845 0.585 20.045 ;
      RECT 0.495 24.695 0.585 31.22 ;
      RECT 0.495 31.41 0.585 38.295 ;
      RECT 0.495 38.555 0.585 42.9 ;
      RECT 0.495 43.16 0.585 43.53 ;
      RECT 0.495 43.79 0.585 44.16 ;
      RECT 0.495 44.42 0.585 48.52 ;
      RECT 0.495 48.78 0.585 77.69 ;
      RECT 0.495 82.69 0.585 91.26 ;
      RECT 0.495 91.59 0.585 91.89 ;
      RECT 0.495 92.22 0.585 92.52 ;
      RECT 0.495 92.85 0.585 93.48 ;
      RECT 0.495 93.81 0.585 94.16 ;
      RECT 0.495 94.49 0.585 94.84 ;
      RECT 0.495 95.17 0.585 95.52 ;
      RECT 0.495 95.85 0.585 96.2 ;
      RECT 0.495 96.53 0.585 96.88 ;
      RECT 0.495 97.21 0.585 97.56 ;
      RECT 0.495 97.89 0.585 98.475 ;
      RECT 0.495 103.39 0.585 104.39 ;
      RECT 0.495 109.39 0.585 110.39 ;
      RECT 0.495 115.39 0.585 116.39 ;
      RECT 0.495 121.39 0.585 122.39 ;
      RECT 0.495 127.14 0.585 129.835 ;
      RECT 0.585 0 0.715 13.8 ;
      RECT 0.585 15.71 0.715 16.935 ;
      RECT 0.585 18.845 0.715 20.045 ;
      RECT 0.585 24.695 0.715 38.295 ;
      RECT 0.585 38.555 0.715 42.9 ;
      RECT 0.585 43.16 0.715 43.53 ;
      RECT 0.585 43.79 0.715 44.16 ;
      RECT 0.585 44.42 0.715 48.52 ;
      RECT 0.585 48.78 0.715 77.69 ;
      RECT 0.585 82.69 0.715 91.26 ;
      RECT 0.585 91.59 0.715 91.89 ;
      RECT 0.585 92.22 0.715 92.52 ;
      RECT 0.585 92.85 0.715 93.48 ;
      RECT 0.585 93.81 0.715 94.16 ;
      RECT 0.585 94.49 0.715 94.84 ;
      RECT 0.585 95.17 0.715 95.52 ;
      RECT 0.585 95.85 0.715 96.2 ;
      RECT 0.585 96.53 0.715 96.88 ;
      RECT 0.585 97.21 0.715 97.56 ;
      RECT 0.585 97.89 0.715 98.475 ;
      RECT 0.585 103.39 0.715 104.39 ;
      RECT 0.585 109.39 0.715 110.39 ;
      RECT 0.585 115.39 0.715 116.39 ;
      RECT 0.585 121.39 0.715 122.39 ;
      RECT 0.585 127.14 0.715 129.835 ;
      RECT 0.715 0 0.915 13.8 ;
      RECT 0.715 15.71 0.915 16.935 ;
      RECT 0.715 18.845 0.915 20.045 ;
      RECT 0.715 24.695 0.915 77.69 ;
      RECT 0.715 82.69 0.915 91.26 ;
      RECT 0.715 91.59 0.915 91.89 ;
      RECT 0.715 92.22 0.915 92.52 ;
      RECT 0.715 92.85 0.915 93.48 ;
      RECT 0.715 93.81 0.915 94.16 ;
      RECT 0.715 94.49 0.915 94.84 ;
      RECT 0.715 95.17 0.915 95.52 ;
      RECT 0.715 95.85 0.915 96.2 ;
      RECT 0.715 96.53 0.915 96.88 ;
      RECT 0.715 97.21 0.915 97.56 ;
      RECT 0.715 97.89 0.915 98.475 ;
      RECT 0.715 103.39 0.915 104.39 ;
      RECT 0.715 109.39 0.915 110.39 ;
      RECT 0.715 115.39 0.915 116.39 ;
      RECT 0.715 121.39 0.915 122.39 ;
      RECT 0.715 127.14 0.915 129.835 ;
      RECT 0.915 0 1.435 13.8 ;
      RECT 0.915 15.71 1.435 16.935 ;
      RECT 0.915 18.845 1.435 20.045 ;
      RECT 0.915 24.695 1.435 77.69 ;
      RECT 0.915 82.69 1.435 98.475 ;
      RECT 0.915 103.39 1.435 104.39 ;
      RECT 0.915 109.39 1.435 110.39 ;
      RECT 0.915 115.39 1.435 116.39 ;
      RECT 0.915 121.39 1.435 122.39 ;
      RECT 0.915 127.14 1.435 129.835 ;
      RECT 1.435 0 2.5 20.045 ;
      RECT 1.435 24.695 2.5 77.69 ;
      RECT 1.435 82.69 2.5 98.475 ;
      RECT 1.435 103.39 2.5 104.39 ;
      RECT 1.435 109.39 2.5 110.39 ;
      RECT 1.435 115.39 2.5 116.39 ;
      RECT 1.435 121.39 2.5 122.39 ;
      RECT 1.435 127.14 2.5 129.835 ;
      RECT 2.5 0 154.165 129.835 ;
      RECT 154.165 0.755 154.885 129.835 ;
      RECT 154.885 0 156.875 129.835 ;
      RECT 156.875 0.715 157.18 129.835 ;
      RECT 157.18 0 159.385 129.835 ;
      RECT 159.385 0.715 159.69 129.835 ;
      RECT 159.69 0 161.89 129.835 ;
      RECT 161.89 0.715 162.195 129.835 ;
      RECT 162.195 0 164.425 129.835 ;
      RECT 164.425 0.715 164.73 129.835 ;
      RECT 164.73 0 166.94 129.835 ;
      RECT 166.94 0.715 167.245 129.835 ;
      RECT 167.245 0 169.42 129.835 ;
      RECT 169.42 0.715 169.72 129.835 ;
      RECT 169.72 0 174.5 129.835 ;
      RECT 174.5 0.395 174.73 129.835 ;
      RECT 174.73 0 501.565 129.835 ;
      RECT 501.565 0 502.505 11.35 ;
      RECT 501.565 13.35 502.505 14.47 ;
      RECT 501.565 16.47 502.505 129.835 ;
      RECT 502.505 0 503 10.64 ;
      RECT 502.505 10.92 503 11.35 ;
      RECT 502.505 13.35 503 13.77 ;
      RECT 502.505 14.05 503 14.47 ;
      RECT 502.505 16.47 503 16.9 ;
      RECT 502.505 17.18 503 129.835 ;
    LAYER met4 ;
      RECT 0 0 190.37 129.835 ;
      RECT 190.37 1.39 191.37 129.835 ;
      RECT 191.37 0 199.905 129.835 ;
      RECT 199.905 1.39 200.905 129.835 ;
      RECT 200.905 0 503 129.835 ;
    LAYER met5 ;
      RECT 0 0 503 129.835 ;
  END
END CF_ADC_SAR12_sar_refs

END LIBRARY
